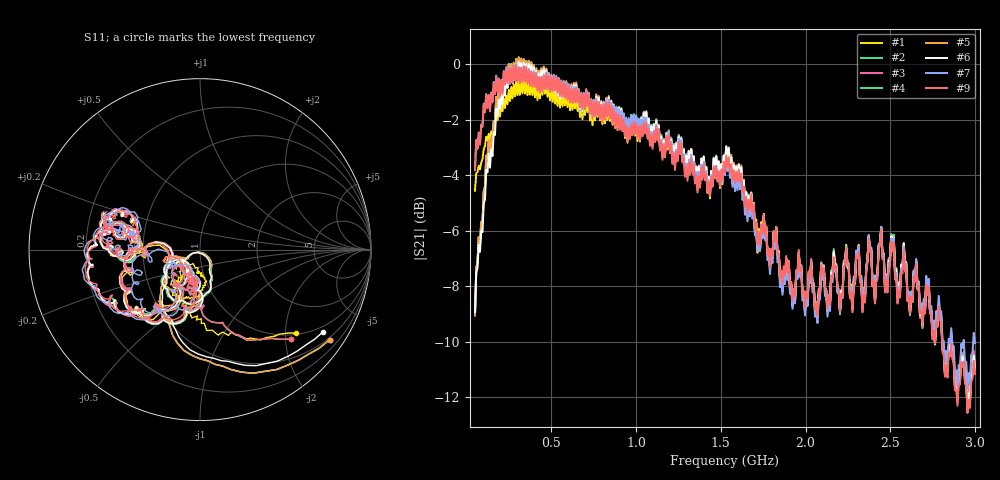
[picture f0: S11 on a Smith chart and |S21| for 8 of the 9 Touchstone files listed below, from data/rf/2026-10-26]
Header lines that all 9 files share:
! NanoVNA-F_V2 fw 0.6.0 SN 4A3639384505514B
! cal: load open short thru cal'ed  over 50000000-3000000000 Hz, 201 points
! points 401, avg 4
# HZ S RI R 50
! S12 and S22 are not measured (written as 0)
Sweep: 50 MHz to 3 GHz
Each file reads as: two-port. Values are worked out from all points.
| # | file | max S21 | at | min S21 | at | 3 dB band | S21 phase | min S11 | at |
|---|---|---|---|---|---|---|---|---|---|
| 1 | tem_h20_nanox_u1_ref_r0c0_i1.s2p | -0.49 dB | 455.6 MHz | -12.3 dB | 2.956 GHz | 94.25 MHz-1.223 GHz | -153 deg at 1.525 GHz | -20.8 dB | 367.1 MHz |
| 2 | tem_h20_nanox_u1_ref_r0c0_i2.s2p | 0.24 dB | 308.1 MHz | -12.3 dB | 2.956 GHz | 160.6 MHz-1.134 GHz | -155 deg at 1.525 GHz | -35.6 dB | 359.8 MHz |
| 3 | tem_h20_nanox_u1_ref_r0c0_i3.s2p | 0.24 dB | 308.1 MHz | -12.2 dB | 2.956 GHz | 160.6 MHz-1.134 GHz | -154 deg at 1.525 GHz | -35.5 dB | 359.8 MHz |
| 4 | tem_h20_nanox_u1_ref_r0c0_i4.s2p | 0.26 dB | 308.1 MHz | -12.4 dB | 2.956 GHz | 160.6 MHz-1.134 GHz | -155 deg at 1.525 GHz | -36.1 dB | 359.8 MHz |
| 5 | tem_h20_nanox_u1_ref_r0c0_i5.s2p | 0.26 dB | 308.1 MHz | -12.5 dB | 2.956 GHz | 160.6 MHz-1.09 GHz | -154 deg at 1.525 GHz | -34.8 dB | 359.8 MHz |
| 6 | tem_h20_nanox_u1_ref_r0c0_i6.s2p | 0.10 dB | 308.1 MHz | -12.4 dB | 2.956 GHz | 160.6 MHz-1.134 GHz | -155 deg at 1.525 GHz | -31.9 dB | 359.8 MHz |
| 7 | tem_h20_nanox_u1_ref_r0x20_1.s2p | 0.01 dB | 293.4 MHz | -11.6 dB | 2.897 GHz | 72.12 MHz-1.134 GHz | -158 deg at 1.525 GHz | -18.9 dB | 883.4 MHz |
| 8 | tem_h20_nanox_u1_ref_r0y20_1.s2p | -0.08 dB | 293.4 MHz | -11.9 dB | 2.897 GHz | 72.12 MHz-1.149 GHz | -158 deg at 1.525 GHz | -16.9 dB | 1.569 GHz |
| 9 | tem_h20_nanox_u1_ref_r90c0_1.s2p | -0.02 dB | 293.4 MHz | -12.6 dB | 2.956 GHz | 72.12 MHz-1.09 GHz | -156 deg at 1.525 GHz | -18.0 dB | 883.4 MHz |
